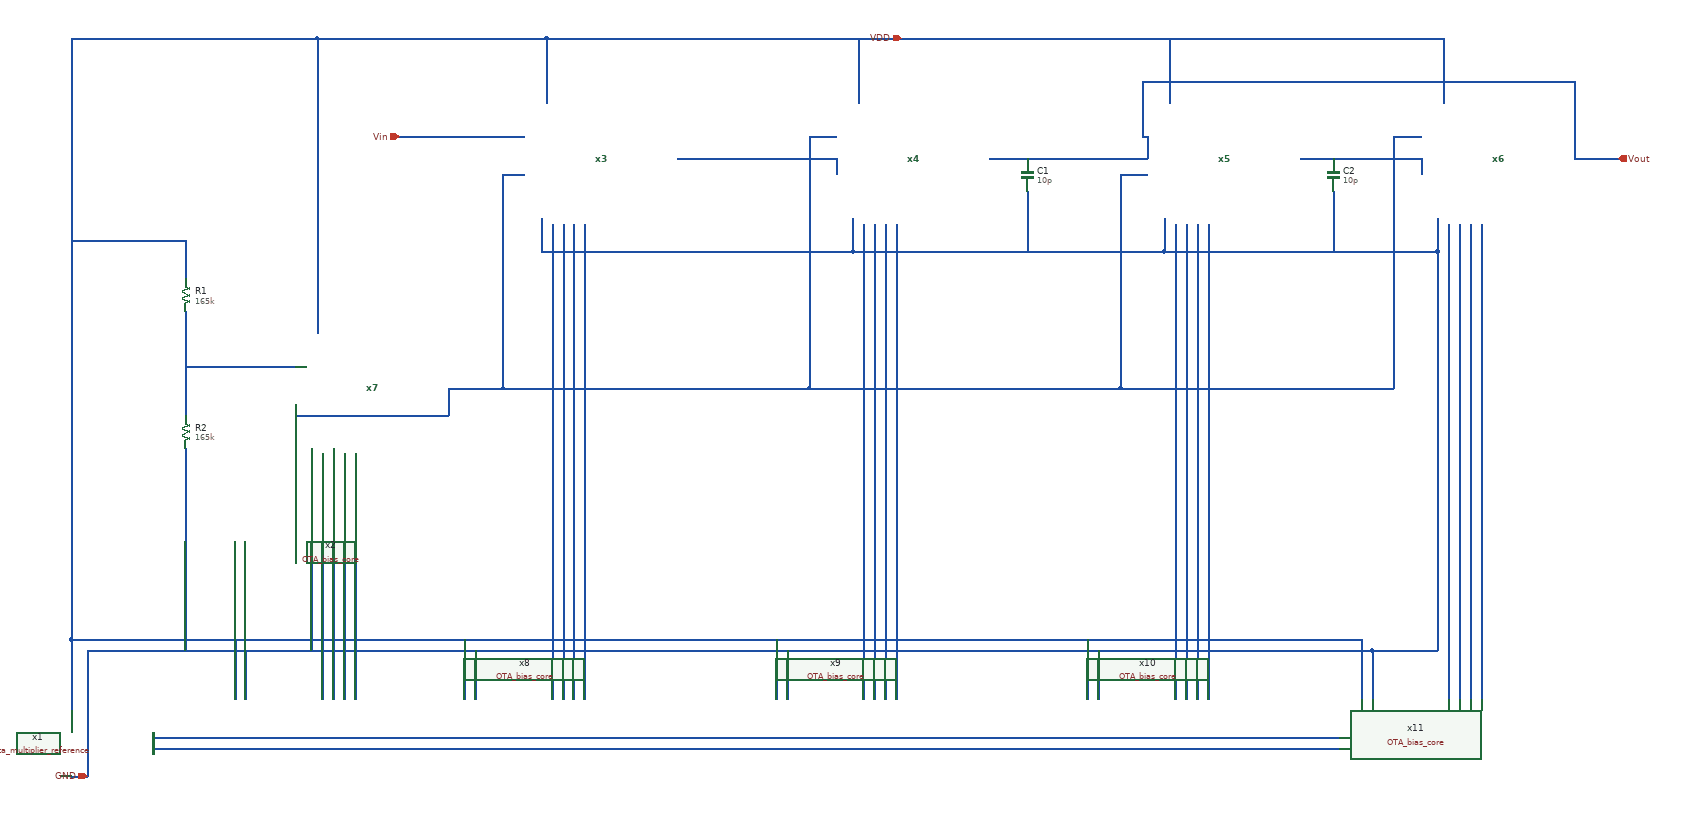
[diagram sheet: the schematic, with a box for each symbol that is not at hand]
v {xschem version=3.4.8RC file_version=1.3}
G {}
K {}
V {}
S {}
F {}
E {}
N -30 -1030 200 -1030 {lab=Vin}
N -220 -540 -220 -520 {lab=#net1}
N -220 -520 60 -520 {lab=#net1}
N 60 -570 60 -520 {lab=#net1}
N 480 -990 770 -990 {lab=#net2}
N 770 -990 770 -960 {lab=#net2}
N 1620 -990 1840 -990 {lab=#net3}
N 1840 -990 1840 -960 {lab=#net3}
N 1050 -990 1340 -990 {lab=Vout}
N 1340 -1030 1340 -990 {lab=Vout}
N 160 -960 200 -960 {lab=#net1}
N 160 -960 160 -570 {lab=#net1}
N 60 -570 160 -570 {lab=#net1}
N 720 -1030 770 -1030 {lab=#net1}
N 720 -1030 720 -570 {lab=#net1}
N 160 -570 720 -570 {lab=#net1}
N 1290 -960 1340 -960 {lab=#net1}
N 720 -570 1290 -570 {lab=#net1}
N 1290 -960 1290 -570 {lab=#net1}
N 1790 -1030 1840 -1030 {lab=#net1}
N 1790 -1030 1790 -570 {lab=#net1}
N 1290 -570 1790 -570 {lab=#net1}
N 240 -1210 240 -1090 {lab=VDD}
N 1880 -1210 1880 -1090 {lab=VDD}
N 240 -1210 1880 -1210 {lab=VDD}
N 810 -1210 810 -1090 {lab=VDD}
N 1380 -1210 1380 -1090 {lab=VDD}
N -180 -1210 -180 -670 {lab=VDD}
N -180 -1210 240 -1210 {lab=VDD}
N 230 -880 230 -820 {lab=GND}
N 230 -820 800 -820 {lab=GND}
N 800 -880 800 -820 {lab=GND}
N 800 -820 1370 -820 {lab=GND}
N 1370 -880 1370 -820 {lab=GND}
N 1370 -820 1870 -820 {lab=GND}
N 1870 -880 1870 -820 {lab=GND}
N 1120 -930 1120 -820 {lab=GND}
N 1680 -930 1680 -820 {lab=GND}
N 2120 -1130 2120 -990 {lab=Vout}
N 1330 -1130 2120 -1130 {lab=Vout}
N 1330 -1130 1330 -1030 {lab=Vout}
N 1330 -1030 1340 -1030 {lab=Vout}
N 2120 -990 2200 -990 {lab=Vout}
N -170 -450 -170 -0 {lab=#net4}
N -150 -460 -150 -0 {lab=#net5}
N -130 -450 -130 -0 {lab=#net6}
N -110 -450 -110 -0 {lab=#net7}
N 250 -870 250 0 {lab=#net8}
N 270 -870 270 0 {lab=#net9}
N 290 -870 290 -0 {lab=#net10}
N 310 -870 310 -0 {lab=#net11}
N 820 -870 820 0 {lab=#net12}
N 840 -870 840 0 {lab=#net13}
N 860 -870 860 0 {lab=#net14}
N 880 -870 880 0 {lab=#net15}
N 1390 -870 1390 0 {lab=#net16}
N 1410 -870 1410 0 {lab=#net17}
N 1430 -870 1430 0 {lab=#net18}
N 1450 -870 1450 0 {lab=#net19}
N 1890 -870 1890 0 {lab=#net20}
N 1910 -870 1910 0 {lab=#net21}
N 1930 -870 1930 0 {lab=#net22}
N 1950 -870 1950 0 {lab=#net23}
N 1190 70 1690 70 {lab=#net24}
N 1190 90 1690 90 {lab=#net25}
N 620 70 1190 70 {lab=#net24}
N 620 90 1190 90 {lab=#net25}
N 50 70 620 70 {lab=#net24}
N 50 90 620 90 {lab=#net25}
N -370 70 50 70 {lab=#net24}
N -370 90 50 90 {lab=#net25}
N -480 70 -370 70 {lab=#net24}
N -480 60 -480 70 {lab=#net24}
N -480 90 -370 90 {lab=#net25}
N -480 90 -480 100 {lab=#net25}
N 1730 -110 1730 -0 {lab=VDD}
N -90 -110 1730 -110 {lab=VDD}
N 1750 -90 1750 -0 {lab=GND}
N -80 -90 1750 -90 {lab=GND}
N 1230 -110 1230 -0 {lab=VDD}
N 1250 -90 1250 0 {lab=GND}
N 680 -90 680 -0 {lab=GND}
N 660 -110 660 -0 {lab=VDD}
N 110 -90 110 -0 {lab=GND}
N 90 -110 90 -0 {lab=VDD}
N -630 -110 -90 -110 {lab=VDD}
N -630 -110 -630 20 {lab=VDD}
N -630 140 -600 140 {lab=GND}
N -600 -90 -600 140 {lab=GND}
N -600 -90 -80 -90 {lab=GND}
N -330 -110 -330 -0 {lab=VDD}
N -310 -90 -310 -0 {lab=GND}
N -630 -1210 -630 -110 {lab=VDD}
N -630 -1210 -180 -1210 {lab=VDD}
N 1870 -820 1870 -90 {lab=GND}
N 1750 -90 1870 -90 {lab=GND}
N -630 -840 -420 -840 {lab=VDD}
N -420 -840 -420 -770 {lab=VDD}
N -420 -710 -420 -520 {lab=#net26}
N -420 -460 -420 -90 {lab=GND}
N -190 -460 -190 -90 {lab=GND}
N -420 -610 -220 -610 {lab=#net26}
C {AURA-Event-Driven-Mixed-Signal-ASIC-for-Acoustic-Pattern-Detection/analog/beta_multiplier_reference.sym} -630 80 0 0 {name=x1 length=410u}
C {AURA-Event-Driven-Mixed-Signal-ASIC-for-Acoustic-Pattern-Detection/analog/folded_cascode_OTA.sym} 330 -990 0 0 {name=x3}
C {AURA-Event-Driven-Mixed-Signal-ASIC-for-Acoustic-Pattern-Detection/analog/folded_cascode_OTA.sym} 900 -990 0 0 {name=x4}
C {AURA-Event-Driven-Mixed-Signal-ASIC-for-Acoustic-Pattern-Detection/analog/folded_cascode_OTA.sym} 1470 -990 0 0 {name=x5}
C {AURA-Event-Driven-Mixed-Signal-ASIC-for-Acoustic-Pattern-Detection/analog/folded_cascode_OTA.sym} 1970 -990 0 0 {name=x6}
C {AURA-Event-Driven-Mixed-Signal-ASIC-for-Acoustic-Pattern-Detection/analog/OTA_bias_core.sym} -220 80 0 0 {name=x2 ratio=1}
C {AURA-Event-Driven-Mixed-Signal-ASIC-for-Acoustic-Pattern-Detection/analog/folded_cascode_OTA.sym} -90 -570 0 0 {name=x7}
C {capa.sym} 1120 -960 0 0 {name=C1
m=1
value=10p
footprint=1206
device="ceramic capacitor"}
C {capa.sym} 1680 -960 0 0 {name=C2
m=1
value=10p
footprint=1206
device="ceramic capacitor"}
C {AURA-Event-Driven-Mixed-Signal-ASIC-for-Acoustic-Pattern-Detection/analog/OTA_bias_core.sym} 200 80 0 0 {name=x8 ratio=1}
C {AURA-Event-Driven-Mixed-Signal-ASIC-for-Acoustic-Pattern-Detection/analog/OTA_bias_core.sym} 770 80 0 0 {name=x9 ratio=1}
C {AURA-Event-Driven-Mixed-Signal-ASIC-for-Acoustic-Pattern-Detection/analog/OTA_bias_core.sym} 1340 80 0 0 {name=x10 ratio=1}
C {AURA-Event-Driven-Mixed-Signal-ASIC-for-Acoustic-Pattern-Detection/analog/OTA_bias_core.sym} 1840 80 0 0 {name=x11 ratio=1}
C {res.sym} -420 -740 0 0 {name=R1
value=165k
footprint=1206
device=resistor
m=1}
C {res.sym} -420 -490 0 0 {name=R2
value=165k
footprint=1206
device=resistor
m=1}
C {iopin.sym} 890 -1210 3 0 {name=p1 lab=VDD}
C {iopin.sym} -600 140 1 0 {name=p2 lab=GND}
C {ipin.sym} -30 -1030 0 0 {name=p3 lab=Vin}
C {opin.sym} 2200 -990 0 0 {name=p4 lab=Vout}
